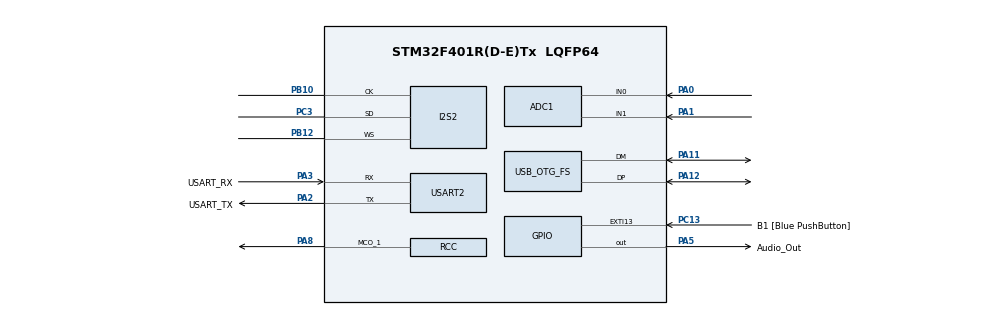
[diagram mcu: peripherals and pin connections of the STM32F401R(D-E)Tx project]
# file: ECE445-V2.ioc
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ADC1.Channel-2\#ChannelRegularConversion=ADC_CHANNEL_0
ADC1.ContinuousConvMode=ENABLE
ADC1.NbrOfConversionFlag=1
ADC1.Rank-2\#ChannelRegularConversion=1
ADC1.SamplingTime-2\#ChannelRegularConversion=ADC_SAMPLETIME_3CYCLES
ADC1.master=1
Dma.Request0=SPI2_TX
Dma.SPI2_TX.0.Direction=DMA_MEMORY_TO_PERIPH
Dma.SPI2_TX.0.FIFOMode=DMA_FIFOMODE_DISABLE
Dma.SPI2_TX.0.Instance=DMA1_Stream4
Dma.SPI2_TX.0.MemDataAlignment=DMA_MDATAALIGN_HALFWORD
Dma.SPI2_TX.0.MemInc=DMA_MINC_ENABLE
Dma.SPI2_TX.0.Mode=DMA_CIRCULAR
Dma.SPI2_TX.0.PeriphDataAlignment=DMA_PDATAALIGN_HALFWORD
Dma.SPI2_TX.0.PeriphInc=DMA_PINC_DISABLE
Dma.SPI2_TX.0.Priority=DMA_PRIORITY_VERY_HIGH
I2S2.AudioFreq=I2S_AUDIOFREQ_48K
I2S2.ErrorAudioFreq=-1.35 %
I2S2.FullDuplexMode=I2S_FULLDUPLEXMODE_DISABLE
I2S2.Instance=SPI$Index
I2S2.RealAudioFreq=47.348 KHz
I2S2.VirtualMode=I2S_MODE_MASTER
Mcu.Family=STM32F4
Mcu.Name=STM32F401R(D-E)Tx
Mcu.Package=LQFP64
NVIC.DMA1_Stream4_IRQn=true\:0\:0\:true\:false\:true\:false\:true\:true
NVIC.OTG_FS_IRQn=true\:0\:0\:false\:false\:true\:false\:true\:true
NVIC.PriorityGroup=NVIC_PRIORITYGROUP_0
PA0-WKUP.Signal=ADCx_IN0
PA1.Signal=ADCx_IN1
PA11.Mode=Host_Only
PA11.Signal=USB_OTG_FS_DM
PA12.Mode=Host_Only
PA12.Signal=USB_OTG_FS_DP
PA13.GPIO_Label=TMS
PA13.Mode=Serial_Wire
PA13.Signal=SYS_JTMS-SWDIO
PA14.GPIO_Label=TCK
PA14.Mode=Serial_Wire
PA14.Signal=SYS_JTCK-SWCLK
PA2.GPIO_Label=USART_TX
PA2.GPIO_Mode=GPIO_MODE_AF_PP
PA2.GPIO_PuPd=GPIO_NOPULL
PA2.GPIO_Speed=GPIO_SPEED_FREQ_LOW
PA2.Mode=Asynchronous
PA2.Signal=USART2_TX
PA3.GPIO_Label=USART_RX
PA3.GPIO_Mode=GPIO_MODE_AF_PP
PA3.GPIO_PuPd=GPIO_NOPULL
PA3.GPIO_Speed=GPIO_SPEED_FREQ_LOW
PA3.Mode=Asynchronous
PA3.Signal=USART2_RX
PA5.GPIO_Label=Audio_Out
PA5.GPIO_Mode=GPIO_MODE_OUTPUT_PP
PA5.GPIO_PuPd=GPIO_NOPULL
PA5.GPIO_Speed=GPIO_SPEED_FREQ_VERY_HIGH
PA5.Signal=GPIO_Output
PA8.Mode=Clock-out-1
PA8.Signal=RCC_MCO_1
PB10.Mode=Half_Duplex_Master
PB10.Signal=I2S2_CK
PB12.Mode=Half_Duplex_Master
PB12.Signal=I2S2_WS
PB3.GPIO_Label=SWO
PB3.Signal=SYS_JTDO-SWO
PC13-ANTI_TAMP.GPIO_Label=B1 [Blue PushButton]
PC13-ANTI_TAMP.GPIO_ModeDefaultEXTI=GPIO_MODE_IT_FALLING
PC13-ANTI_TAMP.GPIO_PuPd=GPIO_NOPULL
PC13-ANTI_TAMP.Signal=GPXTI13
PC14-OSC32_IN.Signal=RCC_OSC32_IN
PC15-OSC32_OUT.Signal=RCC_OSC32_OUT
PC3.Mode=Half_Duplex_Master
PC3.Signal=I2S2_SD
PH0\ -\ OSC_IN.Mode=HSE-External-Oscillator
PH0\ -\ OSC_IN.Signal=RCC_OSC_IN
PH1\ -\ OSC_OUT.Mode=HSE-External-Oscillator
PH1\ -\ OSC_OUT.Signal=RCC_OSC_OUT
ProjectManager.HeapSize=0x200
ProjectManager.StackSize=0x400
ProjectManager.TargetToolchain=STM32CubeIDE
RCC.48MHZClocksFreq_Value=48000000
RCC.AHBFreq_Value=48000000
RCC.APB1CLKDivider=RCC_HCLK_DIV2
RCC.APB1Freq_Value=24000000
RCC.APB1TimFreq_Value=48000000
RCC.APB2Freq_Value=48000000
RCC.APB2TimFreq_Value=48000000
RCC.CortexFreq_Value=48000000
RCC.EXTERNAL_CLOCK_VALUE=12288000
RCC.HCLKFreq_Value=48000000
RCC.HSE_VALUE=8000000
RCC.HSI_VALUE=16000000
RCC.LSE_VALUE=0
RCC.PLLI2SN=50
RCC.PLLM=4
RCC.PLLN=96
RCC.PLLP=RCC_PLLP_DIV4
RCC.SYSCLKFreq_VALUE=48000000
RCC.SYSCLKSource=RCC_SYSCLKSOURCE_PLLCLK
RCC.VCOOutputFreq_Value=192000000
SH.ADCx_IN0.0=ADC1_IN0,IN0
SH.ADCx_IN1.0=ADC1_IN1,IN1
USART2.VirtualMode=VM_ASYNC
USB_HOST.SW_VBUS_DRIVE_AUDIO_FS=true
USB_HOST.USBH_HandleTypeDef-AUDIO_FS=hUsbHostFS
USB_HOST.VirtualModeFS=Audio
USB_OTG_FS.Sof_enable=DISABLE
USB_OTG_FS.VirtualMode=Host_Only
USB_OTG_FS.phy_itface=HCD_PHY_EMBEDDED
VP_USB_HOST_VS_USB_HOST_AUDIO_FS.Mode=AUDIO_FS
board=NUCLEO-F401RE

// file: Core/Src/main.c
/* USER CODE BEGIN Header */
/**
  ******************************************************************************
  * @file           : main.c
  * @brief          : Main program body
  ******************************************************************************
  * @attention
  *
  * Copyright (c) 2024 STMicroelectronics.
  * All rights reserved.
  *
  * This software is licensed under terms that can be found in the LICENSE file
  * in the root directory of this software component.
  * If no LICENSE file comes with this software, it is provided AS-IS.
  *
  ******************************************************************************
  */
/* USER CODE END Header */
#include "main.h"

/* USER CODE BEGIN PD */
#define BUFFER_SIZE 256

/* USER CODE END PD */

ADC_HandleTypeDef hadc1;

I2S_HandleTypeDef hi2s2;
DMA_HandleTypeDef hdma_spi2_tx;

UART_HandleTypeDef huart2;

/* USER CODE BEGIN PV */
uint32_t last_adc_value = 0;
uint32_t current_adc_value = 0;
/* USER CODE END PV */

void SystemClock_Config(void);
static void MX_GPIO_Init(void);
static void MX_DMA_Init(void);
static void MX_USART2_UART_Init(void);
static void MX_ADC1_Init(void);
static void MX_I2S2_Init(void);
/* USER CODE BEGIN PFP */

int16_t audioBuffer[BUFFER_SIZE];
static volatile int16_t* audioBufferPtr = &audioBuffer[0];

uint8_t dataReadyFlag;

/* USER CODE END PFP */

/* USER CODE BEGIN 0 */
void HAL_I2SEx_TxRxHalfCpltCallBack(I2S_HandleTypeDef *hi2s)
{
	audioBufferPtr = &audioBuffer[0];
	dataReadyFlag = 1;
}

void HAL_I2SEx_TxRxCpltCallBack(I2S_HandleTypeDef *hi2s)
{
	audioBufferPtr = &audioBuffer[BUFFER_SIZE];
	dataReadyFlag = 1;
}

void GetNextBuffer()
{
	for (uint16_t i = 0; i < (BUFFER_SIZE / 2) - 1; i += 2)
	{
		const double sample = (double)((1 << 16) - 1) * ((double)(i) / (double)(BUFFER_SIZE));
		audioBufferPtr[i]   = (int16_t)(sample); // left
		audioBufferPtr[i+1] = (int16_t)(sample); // right
	}
	dataReadyFlag = 0;
}

void InitAudioBuffer()
{
	HAL_StatusTypeDef status = HAL_I2SEx_TransmitReceive_DMA(&hi2s2, (uint16_t*)audioBufferPtr, NULL, BUFFER_SIZE);
}

void Loop()
{
	if (dataReadyFlag)
	{
		GetNextBuffer();
	}
}
/**
  * @brief  Redirects printf output to UART.
  * @param  ch: The character to output.
  * @retval The character written to the UART.
  */
int __io_putchar(int ch)
{
  // Send the character via UART
  HAL_UART_Transmit(&huart2, (uint8_t*)&ch, 1, HAL_MAX_DELAY);
  return ch;
}

/* USER CODE END 0 */

int main(void)
{

  /* MCU Configuration--------------------------------------------------------*/

  /* Reset of all peripherals, Initializes the Flash interface and the Systick. */
  HAL_Init();

  /* Configure the system clock */
  SystemClock_Config();

  /* Initialize all configured peripherals */
  MX_GPIO_Init();
  MX_DMA_Init();
  MX_USART2_UART_Init();
  MX_ADC1_Init();
  MX_I2S2_Init();
  InitAudioBuffer();

  /* Infinite loop */
  while (1)
  {
	  Loop();
  }
}

void SystemClock_Config(void)
{
  RCC_OscInitTypeDef RCC_OscInitStruct = {0};
  RCC_ClkInitTypeDef RCC_ClkInitStruct = {0};

  /** Macro to configure the PLL multiplication factor
  */
  __HAL_RCC_PLL_PLLM_CONFIG(16);

  /** Macro to configure the PLL clock source
  */
  __HAL_RCC_PLL_PLLSOURCE_CONFIG(RCC_PLLSOURCE_HSI);

  /** Configure the main internal regulator output voltage
  */
  __HAL_RCC_PWR_CLK_ENABLE();
  __HAL_PWR_VOLTAGESCALING_CONFIG(PWR_REGULATOR_VOLTAGE_SCALE2);

  /** Initializes the RCC Oscillators according to the specified parameters
  * in the RCC_OscInitTypeDef structure.
  */
  RCC_OscInitStruct.OscillatorType = RCC_OSCILLATORTYPE_HSI;
  RCC_OscInitStruct.HSIState = RCC_HSI_ON;
  RCC_OscInitStruct.HSICalibrationValue = RCC_HSICALIBRATION_DEFAULT;
  RCC_OscInitStruct.PLL.PLLState = RCC_PLL_NONE;
  RCC_OscInitStruct.PLL.PLLSource = RCC_PLLSOURCE_HSI;
  if (HAL_RCC_OscConfig(&RCC_OscInitStruct) != HAL_OK)
  {
    Error_Handler();
  }

  /** Initializes the CPU, AHB and APB buses clocks
  */
  RCC_ClkInitStruct.ClockType = RCC_CLOCKTYPE_HCLK|RCC_CLOCKTYPE_SYSCLK
                              |RCC_CLOCKTYPE_PCLK1|RCC_CLOCKTYPE_PCLK2;
  RCC_ClkInitStruct.SYSCLKSource = RCC_SYSCLKSOURCE_HSI;
  RCC_ClkInitStruct.AHBCLKDivider = RCC_SYSCLK_DIV1;
  RCC_ClkInitStruct.APB1CLKDivider = RCC_HCLK_DIV2;
  RCC_ClkInitStruct.APB2CLKDivider = RCC_HCLK_DIV1;

  if (HAL_RCC_ClockConfig(&RCC_ClkInitStruct, FLASH_LATENCY_0) != HAL_OK)
  {
    Error_Handler();
  }
  HAL_RCC_MCOConfig(RCC_MCO1, RCC_MCO1SOURCE_HSI, RCC_MCODIV_1);
}

static void MX_ADC1_Init(void)
{

  ADC_ChannelConfTypeDef sConfig = {0};

  /** Configure the global features of the ADC (Clock, Resolution, Data Alignment and number of conversion)
  */
  hadc1.Instance = ADC1;
  hadc1.Init.ClockPrescaler = ADC_CLOCK_SYNC_PCLK_DIV2;
  hadc1.Init.Resolution = ADC_RESOLUTION_12B;
  hadc1.Init.ScanConvMode = DISABLE;
  hadc1.Init.ContinuousConvMode = ENABLE;
  hadc1.Init.DiscontinuousConvMode = DISABLE;
  hadc1.Init.ExternalTrigConvEdge = ADC_EXTERNALTRIGCONVEDGE_NONE;
  hadc1.Init.ExternalTrigConv = ADC_SOFTWARE_START;
  hadc1.Init.DataAlign = ADC_DATAALIGN_RIGHT;
  hadc1.Init.NbrOfConversion = 1;
  hadc1.Init.DMAContinuousRequests = DISABLE;
  hadc1.Init.EOCSelection = ADC_EOC_SINGLE_CONV;
  if (HAL_ADC_Init(&hadc1) != HAL_OK)
  {
    Error_Handler();
  }

  /** Configure for the selected ADC regular channel its corresponding rank in the sequencer and its sample time.
  */
  sConfig.Channel = ADC_CHANNEL_0;
  sConfig.Rank = 1;
  sConfig.SamplingTime = ADC_SAMPLETIME_3CYCLES;
  if (HAL_ADC_ConfigChannel(&hadc1, &sConfig) != HAL_OK)
  {
    Error_Handler();
  }

}

static void MX_I2S2_Init(void)
{

  hi2s2.Instance = SPI2;
  hi2s2.Init.Mode = I2S_MODE_MASTER_TX;
  hi2s2.Init.Standard = I2S_STANDARD_PHILIPS;
  hi2s2.Init.DataFormat = I2S_DATAFORMAT_16B;
  hi2s2.Init.MCLKOutput = I2S_MCLKOUTPUT_DISABLE;
  hi2s2.Init.AudioFreq = I2S_AUDIOFREQ_8K;
  hi2s2.Init.CPOL = I2S_CPOL_LOW;
  hi2s2.Init.ClockSource = I2S_CLOCK_PLL;
  hi2s2.Init.FullDuplexMode = I2S_FULLDUPLEXMODE_DISABLE;
  if (HAL_I2S_Init(&hi2s2) != HAL_OK)
  {
    Error_Handler();
  }

}

static void MX_USART2_UART_Init(void)
{

  huart2.Instance = USART2;
  huart2.Init.BaudRate = 115200;
  huart2.Init.WordLength = UART_WORDLENGTH_8B;
  huart2.Init.StopBits = UART_STOPBITS_1;
  huart2.Init.Parity = UART_PARITY_NONE;
  huart2.Init.Mode = UART_MODE_TX_RX;
  huart2.Init.HwFlowCtl = UART_HWCONTROL_NONE;
  huart2.Init.OverSampling = UART_OVERSAMPLING_16;
  if (HAL_UART_Init(&huart2) != HAL_OK)
  {
    Error_Handler();
  }

}

static void MX_DMA_Init(void)
{

  /* DMA controller clock enable */
  __HAL_RCC_DMA1_CLK_ENABLE();

  /* DMA interrupt init */
  /* DMA1_Stream4_IRQn interrupt configuration */
  HAL_NVIC_SetPriority(DMA1_Stream4_IRQn, 0, 0);
  HAL_NVIC_EnableIRQ(DMA1_Stream4_IRQn);

}

static void MX_GPIO_Init(void)
{
  GPIO_InitTypeDef GPIO_InitStruct = {0};

  /* GPIO Ports Clock Enable */
  __HAL_RCC_GPIOC_CLK_ENABLE();
  __HAL_RCC_GPIOH_CLK_ENABLE();
  __HAL_RCC_GPIOA_CLK_ENABLE();
  __HAL_RCC_GPIOB_CLK_ENABLE();

  /*Configure GPIO pin Output Level */
  HAL_GPIO_WritePin(Audio_Out_GPIO_Port, Audio_Out_Pin, GPIO_PIN_RESET);

  /*Configure GPIO pin : B1_Pin */
  GPIO_InitStruct.Pin = B1_Pin;
  GPIO_InitStruct.Mode = GPIO_MODE_IT_FALLING;
  GPIO_InitStruct.Pull = GPIO_NOPULL;
  HAL_GPIO_Init(B1_GPIO_Port, &GPIO_InitStruct);

  /*Configure GPIO pin : Audio_Out_Pin */
  GPIO_InitStruct.Pin = Audio_Out_Pin;
  GPIO_InitStruct.Mode = GPIO_MODE_OUTPUT_PP;
  GPIO_InitStruct.Pull = GPIO_NOPULL;
  GPIO_InitStruct.Speed = GPIO_SPEED_FREQ_VERY_HIGH;
  HAL_GPIO_Init(Audio_Out_GPIO_Port, &GPIO_InitStruct);

  /*Configure GPIO pin : PA8 */
  GPIO_InitStruct.Pin = GPIO_PIN_8;
  GPIO_InitStruct.Mode = GPIO_MODE_AF_PP;
  GPIO_InitStruct.Pull = GPIO_NOPULL;
  GPIO_InitStruct.Speed = GPIO_SPEED_FREQ_LOW;
  GPIO_InitStruct.Alternate = GPIO_AF0_MCO;
  HAL_GPIO_Init(GPIOA, &GPIO_InitStruct);

}

void Error_Handler(void)
{
  __disable_irq();
  while (1)
  {
  }
}
